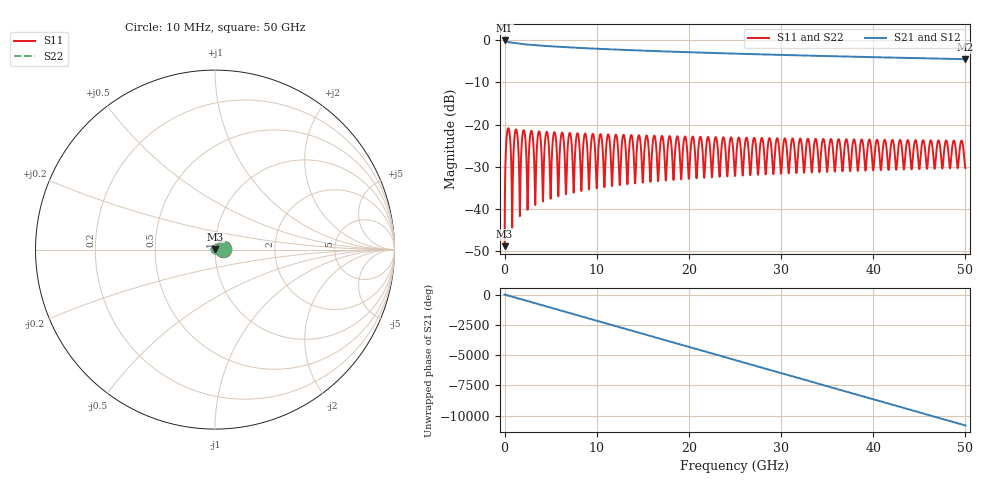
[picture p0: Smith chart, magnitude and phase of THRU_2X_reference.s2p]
! 2x-thru exact (fixture A + fixture A retourne) : Fixture A synthetique : ligne Zc=55.0 ohm, delai=300 ps, pertes 1.0 dB @10 GHz (~sqrt(f)), eps_r_eff=3.0 -> 51.93 mm, Z0=50 ohm
! Frequency(Hz) S11 S21 S12 S22 (Re Im)
# Hz S RI R 50
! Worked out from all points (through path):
!   5000 points, 10 MHz to 50 GHz, reference 50 ohm
!   highest |S21| = -0.06 dB at 10 MHz (marker M1); lowest = -4.5 dB at 50 GHz (marker M2)
!   group delay of S21, straight-line fit = 600 ps
!   lowest |S11| = -48.8 dB at 10 MHz (marker M3), VSWR 1.01, Z = 50.1 + j0.355 ohm
!   |S11| at or under -10 dB: start of sweep to end of sweep
!   |S22| runs from -48.8 to -20.8 dB; largest |S21 - S12| = 9e-17
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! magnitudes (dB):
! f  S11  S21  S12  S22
! 10 MHz  -48.8  -0.1  -0.1  -48.8
! 410 MHz  -20.8  -0.4  -0.4  -20.8
! 830 MHz  -44.4  -0.6  -0.6  -44.4
! 1.25 GHz  -21.1  -0.7  -0.7  -21.1
! 1.66 GHz  -41.5  -0.8  -0.8  -41.5
! 2.08 GHz  -21.3  -0.9  -0.9  -21.3
! 2.49 GHz  -39.7  -1.0  -1.0  -39.7
! 2.92 GHz  -21.5  -1.1  -1.1  -21.5
! 3.32 GHz  -38.5  -1.2  -1.2  -38.5
! 3.75 GHz  -21.6  -1.3  -1.3  -21.6
! 4.15 GHz  -37.5  -1.3  -1.3  -37.5
! 4.58 GHz  -21.7  -1.4  -1.4  -21.7
! 4.98 GHz  -36.7  -1.4  -1.4  -36.7
! 5.42 GHz  -21.8  -1.5  -1.5  -21.8
! 8.35 GHz  -35.3  -1.8  -1.8  -35.3
! 8.75 GHz  -22.1  -1.9  -1.9  -22.1
! 9.16 GHz  -35.3  -1.9  -1.9  -35.3
! 16.68 GHz  -33.3  -2.6  -2.6  -33.3
! 25.01 GHz  -32.1  -3.2  -3.2  -32.1
! 33.34 GHz  -31.3  -3.7  -3.7  -31.3
! 41.67 GHz  -30.7  -4.1  -4.1  -30.7
! 50 GHz  -30.3  -4.5  -4.5  -30.3
